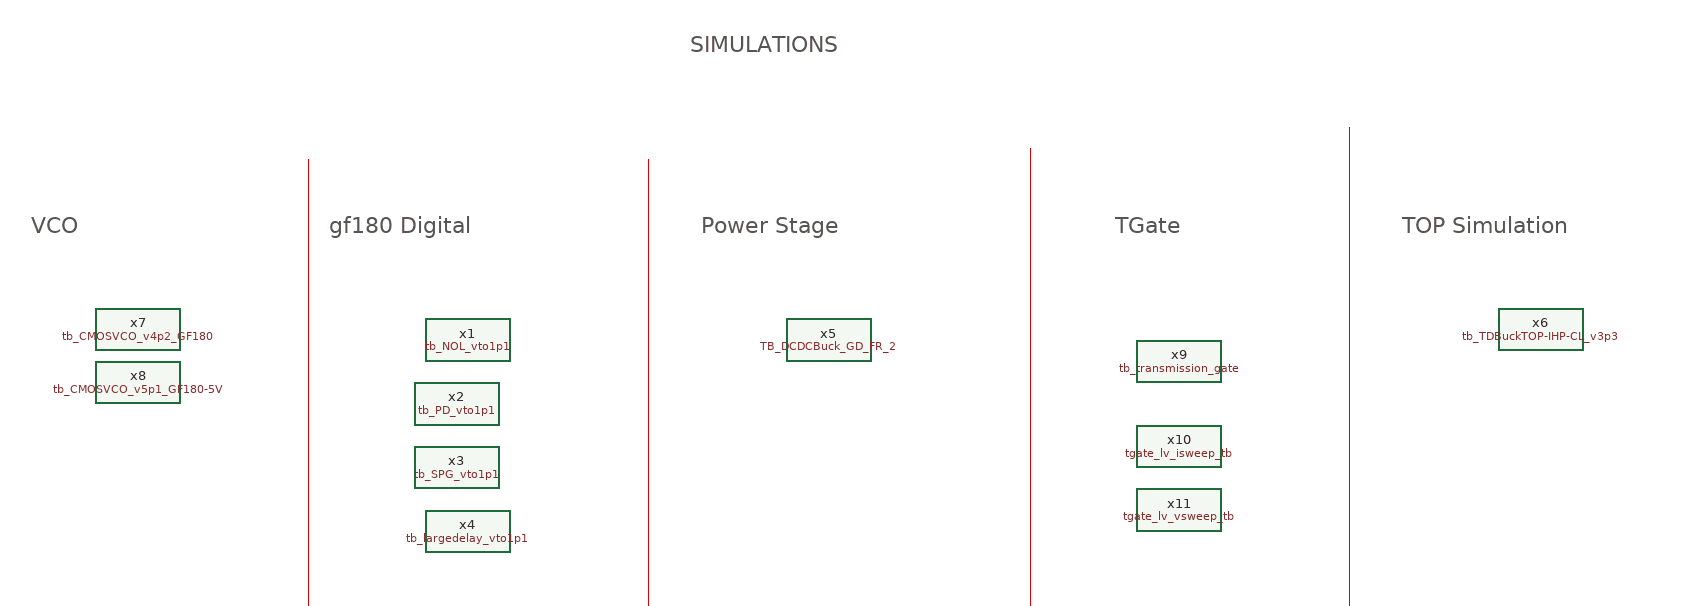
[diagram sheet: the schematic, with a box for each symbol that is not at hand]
v {xschem version=3.4.7 file_version=1.2}
G {}
K {}
V {}
S {}
E {}
L 7 300 -870 300 60 {}
L 7 620 -870 620 60 {}
L 7 980 -880 980 50 {}
L 7 1280 -900 1280 30 {}
L 7 1680 -900 1680 30 {}
L 7 0 -890 0 40 {}
T {VCO} 40 -820 0 0 0.8 0.8 {}
T {gf180 Digital} 320 -820 0 0 0.8 0.8 {}
T {Power Stage} 670 -820 0 0 0.8 0.8 {}
T {TGate} 1060 -820 0 0 0.8 0.8 {}
T {TOP Simulation} 1330 -820 0 0 0.8 0.8 {}
T {SIMULATIONS} 660 -990 0 0 0.8 0.8 {}
C {gf180_digital/NOL/tb_NOL_vto1p1.sym} 450 -700 0 0 {name=x1}
C {gf180_digital/PD/tb_PD_vto1p1.sym} 440 -640 0 0 {name=x2}
C {gf180_digital/SPG/tb_SPG_vto1p1.sym} 440 -580 0 0 {name=x3}
C {gf180_digital/large_delay/tb_largedelay_vto1p1.sym} 450 -520 0 0 {name=x4}
C {pwr_stage/TB_DCDCBuck_GD_FR_2.sym} 790 -700 0 0 {name=x5}
C {top/tb_TDBuckTOP-IHP-CL_v3p3.sym} 1460 -710 0 0 {name=x6}
C {vco/tb_CMOSVCO_v4p2_GF180.sym} 140 -710 0 0 {name=x7}
C {vco/tb_CMOSVCO_v5p1_GF180-5V.sym} 140 -660 0 0 {name=x8}
C {tgate/tb_transmission_gate.sym} 1120 -680 0 0 {name=x9}
C {tgate/tgate_lv_isweep_tb.sym} 1120 -600 0 0 {name=x10}
C {tgate/tgate_lv_vsweep_tb.sym} 1120 -540 0 0 {name=x11}
